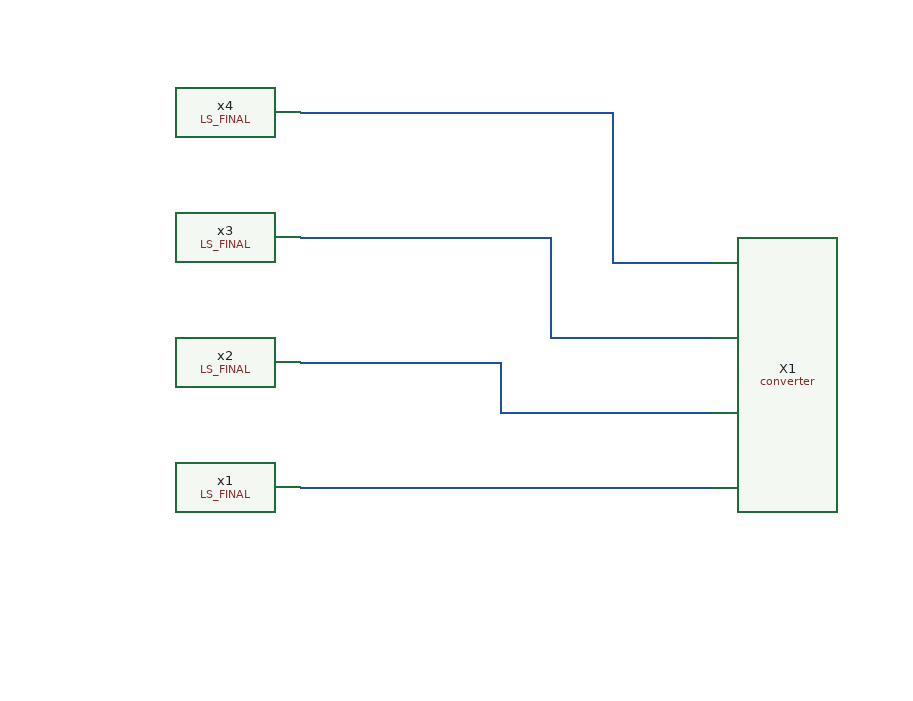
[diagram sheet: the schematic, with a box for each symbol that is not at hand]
v {xschem version=3.0.0 file_version=1.2 }
G {}
K {}
V {}
S {}
E {}
N 320 -40 650 -40 {}
N 320 -140 480 -140 {}
N 480 -140 480 -100 {}
N 480 -100 650 -100 {}
N 320 -240 520 -240 {}
N 520 -240 520 -160 {}
N 520 -160 650 -160 {}
N 320 -340 570 -340 {}
N 570 -340 570 -220 {}
N 570 -220 650 -220 {}
C {personal/3LFCC_AC3E/xschem/hierarchy_sch/converter.sym} 610 60 0 0 {name=X1}
C {personal/3LFCC_AC3E/xschem/dev_switches/DCDC_5V_FINAL/LS_FINAL.sym} 170 -60 0 0 {name=x1}
C {personal/3LFCC_AC3E/xschem/dev_switches/DCDC_5V_FINAL/LS_FINAL.sym} 170 -160 0 0 {name=x2}
C {personal/3LFCC_AC3E/xschem/dev_switches/DCDC_5V_FINAL/LS_FINAL.sym} 170 -260 0 0 {name=x3}
C {personal/3LFCC_AC3E/xschem/dev_switches/DCDC_5V_FINAL/LS_FINAL.sym} 170 -360 0 0 {name=x4}
